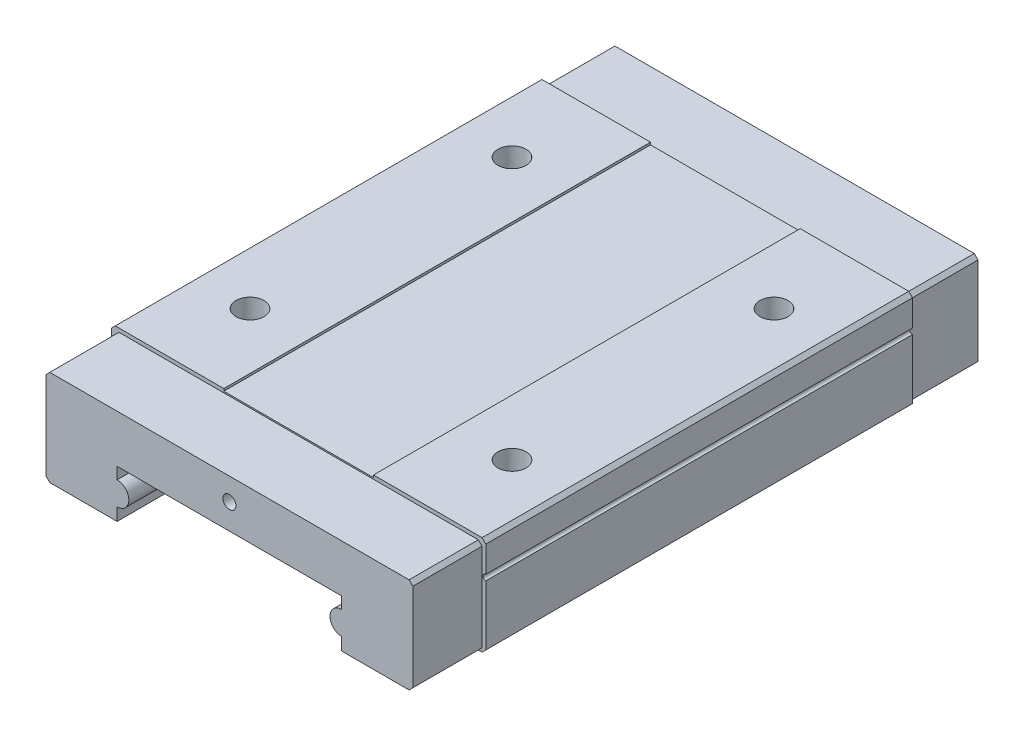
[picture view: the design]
ISO-10303-21;
HEADER;
FILE_DESCRIPTION(('STEP AP214'),'2;1');
FILE_NAME('part.step','',(''),(''),'','','');
FILE_SCHEMA(('AUTOMOTIVE_DESIGN { 1 0 10303 214 1 1 1 1 }'));
ENDSEC;
DATA;
#1=APPLICATION_CONTEXT('core data for automotive mechanical design processes');
#2=APPLICATION_PROTOCOL_DEFINITION('international standard','automotive_design',2000,#1);
#3=PRODUCT_CONTEXT('',#1,'mechanical');
#4=PRODUCT('Part','Part','',(#3));
#5=PRODUCT_RELATED_PRODUCT_CATEGORY('part','',(#4));
#6=PRODUCT_DEFINITION_FORMATION('','',#4);
#7=PRODUCT_DEFINITION_CONTEXT('part definition',#1,'design');
#8=PRODUCT_DEFINITION('design','',#6,#7);
#9=PRODUCT_DEFINITION_SHAPE('','',#8);
#10=(LENGTH_UNIT() NAMED_UNIT(*) SI_UNIT(.MILLI.,.METRE.));
#11=(NAMED_UNIT(*) PLANE_ANGLE_UNIT() SI_UNIT($,.RADIAN.));
#12=(NAMED_UNIT(*) SI_UNIT($,.STERADIAN.) SOLID_ANGLE_UNIT());
#13=UNCERTAINTY_MEASURE_WITH_UNIT(LENGTH_MEASURE(1.E-05),#10,'distance_accuracy_value','');
#14=(GEOMETRIC_REPRESENTATION_CONTEXT(3) GLOBAL_UNCERTAINTY_ASSIGNED_CONTEXT((#13)) GLOBAL_UNIT_ASSIGNED_CONTEXT((#10,
#11,#12)) REPRESENTATION_CONTEXT('',''));
#15=CARTESIAN_POINT('',(0.,0.,0.));
#16=DIRECTION('',(0.,0.,1.));
#17=DIRECTION('',(1.,0.,0.));
#18=AXIS2_PLACEMENT_3D('',#15,#16,#17);
#19=CARTESIAN_POINT('',(-14.,10.4000538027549,-14.));
#20=DIRECTION('',(0.,1.,0.));
#21=DIRECTION('',(0.,0.,1.));
#22=AXIS2_PLACEMENT_3D('',#19,#20,#21);
#23=CONICAL_SURFACE('',#22,1.49996298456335,0.785367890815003);
#24=CARTESIAN_POINT('',(-14.,8.89999999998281,-14.));
#25=VERTEX_POINT('',#24);
#26=VERTEX_LOOP('',#25);
#27=FACE_BOUND('',#26,.T.);
#28=CARTESIAN_POINT('',(-14.,10.4000908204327,-14.));
#29=DIRECTION('',(0.,1.,0.));
#30=DIRECTION('',(0.,0.,1.));
#31=AXIS2_PLACEMENT_3D('',#28,#29,#30);
#32=CIRCLE('',#31,1.5);
#33=CARTESIAN_POINT('',(-14.,10.4000908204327,-12.5));
#34=VERTEX_POINT('',#33);
#35=EDGE_CURVE('E20',#34,#34,#32,.T.);
#36=ORIENTED_EDGE('',*,*,#35,.T.);
#37=EDGE_LOOP('',(#36));
#38=FACE_BOUND('',#37,.T.);
#39=ADVANCED_FACE('F17',(#27,#38),#23,.F.);
#40=CARTESIAN_POINT('',(-14.,10.4000538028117,14.));
#41=DIRECTION('',(0.,1.,0.));
#42=DIRECTION('',(0.,0.,1.));
#43=AXIS2_PLACEMENT_3D('',#40,#41,#42);
#44=CONICAL_SURFACE('',#43,1.49996298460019,0.785367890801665);
#45=CARTESIAN_POINT('',(-14.,8.89999999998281,14.));
#46=VERTEX_POINT('',#45);
#47=VERTEX_LOOP('',#46);
#48=FACE_BOUND('',#47,.T.);
#49=CARTESIAN_POINT('',(-14.,10.4000908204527,14.));
#50=DIRECTION('',(0.,1.,0.));
#51=DIRECTION('',(0.,0.,1.));
#52=AXIS2_PLACEMENT_3D('',#49,#50,#51);
#53=CIRCLE('',#52,1.5);
#54=CARTESIAN_POINT('',(-14.,10.4000908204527,15.5));
#55=VERTEX_POINT('',#54);
#56=EDGE_CURVE('E369',#55,#55,#53,.T.);
#57=ORIENTED_EDGE('',*,*,#56,.T.);
#58=EDGE_LOOP('',(#57));
#59=FACE_BOUND('',#58,.T.);
#60=ADVANCED_FACE('F1261',(#48,#59),#44,.F.);
#61=CARTESIAN_POINT('',(14.,10.4000538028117,14.));
#62=DIRECTION('',(0.,1.,0.));
#63=DIRECTION('',(0.,0.,1.));
#64=AXIS2_PLACEMENT_3D('',#61,#62,#63);
#65=CONICAL_SURFACE('',#64,1.49996298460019,0.785367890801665);
#66=CARTESIAN_POINT('',(14.,8.89999999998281,14.));
#67=VERTEX_POINT('',#66);
#68=VERTEX_LOOP('',#67);
#69=FACE_BOUND('',#68,.T.);
#70=CARTESIAN_POINT('',(14.,10.4000908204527,14.));
#71=DIRECTION('',(0.,1.,0.));
#72=DIRECTION('',(0.,0.,1.));
#73=AXIS2_PLACEMENT_3D('',#70,#71,#72);
#74=CIRCLE('',#73,1.5);
#75=CARTESIAN_POINT('',(14.,10.4000908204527,15.5));
#76=VERTEX_POINT('',#75);
#77=EDGE_CURVE('E362',#76,#76,#74,.T.);
#78=ORIENTED_EDGE('',*,*,#77,.T.);
#79=EDGE_LOOP('',(#78));
#80=FACE_BOUND('',#79,.T.);
#81=ADVANCED_FACE('F440',(#69,#80),#65,.F.);
#82=CARTESIAN_POINT('',(14.,10.4000538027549,-14.));
#83=DIRECTION('',(0.,1.,0.));
#84=DIRECTION('',(0.,0.,1.));
#85=AXIS2_PLACEMENT_3D('',#82,#83,#84);
#86=CONICAL_SURFACE('',#85,1.49996298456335,0.785367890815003);
#87=CARTESIAN_POINT('',(14.,8.89999999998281,-14.));
#88=VERTEX_POINT('',#87);
#89=VERTEX_LOOP('',#88);
#90=FACE_BOUND('',#89,.T.);
#91=CARTESIAN_POINT('',(14.,10.4000908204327,-14.));
#92=DIRECTION('',(0.,1.,0.));
#93=DIRECTION('',(0.,0.,1.));
#94=AXIS2_PLACEMENT_3D('',#91,#92,#93);
#95=CIRCLE('',#94,1.5);
#96=CARTESIAN_POINT('',(14.,10.4000908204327,-12.5));
#97=VERTEX_POINT('',#96);
#98=EDGE_CURVE('E360',#97,#97,#95,.T.);
#99=ORIENTED_EDGE('',*,*,#98,.T.);
#100=EDGE_LOOP('',(#99));
#101=FACE_BOUND('',#100,.T.);
#102=ADVANCED_FACE('F426',(#90,#101),#86,.F.);
#103=CARTESIAN_POINT('',(-14.,14.,-14.));
#104=DIRECTION('',(0.,1.,0.));
#105=DIRECTION('',(0.,0.,1.));
#106=AXIS2_PLACEMENT_3D('',#103,#104,#105);
#107=CYLINDRICAL_SURFACE('',#106,1.5);
#108=CARTESIAN_POINT('',(-14.,14.,-14.));
#109=DIRECTION('',(0.,1.,0.));
#110=DIRECTION('',(0.,0.,1.));
#111=AXIS2_PLACEMENT_3D('',#108,#109,#110);
#112=CIRCLE('',#111,1.5);
#113=CARTESIAN_POINT('',(-14.,14.,-12.5));
#114=VERTEX_POINT('',#113);
#115=EDGE_CURVE('E293',#114,#114,#112,.F.);
#116=ORIENTED_EDGE('',*,*,#115,.F.);
#117=EDGE_LOOP('',(#116));
#118=FACE_BOUND('',#117,.T.);
#119=ORIENTED_EDGE('',*,*,#35,.F.);
#120=EDGE_LOOP('',(#119));
#121=FACE_BOUND('',#120,.T.);
#122=ADVANCED_FACE('F421',(#118,#121),#107,.F.);
#123=CARTESIAN_POINT('',(-14.,14.,14.));
#124=DIRECTION('',(0.,1.,0.));
#125=DIRECTION('',(0.,0.,1.));
#126=AXIS2_PLACEMENT_3D('',#123,#124,#125);
#127=CYLINDRICAL_SURFACE('',#126,1.5);
#128=CARTESIAN_POINT('',(-14.,14.,14.));
#129=DIRECTION('',(0.,1.,0.));
#130=DIRECTION('',(0.,0.,1.));
#131=AXIS2_PLACEMENT_3D('',#128,#129,#130);
#132=CIRCLE('',#131,1.5);
#133=CARTESIAN_POINT('',(-14.,14.,15.5));
#134=VERTEX_POINT('',#133);
#135=EDGE_CURVE('E288',#134,#134,#132,.F.);
#136=ORIENTED_EDGE('',*,*,#135,.F.);
#137=EDGE_LOOP('',(#136));
#138=FACE_BOUND('',#137,.T.);
#139=ORIENTED_EDGE('',*,*,#56,.F.);
#140=EDGE_LOOP('',(#139));
#141=FACE_BOUND('',#140,.T.);
#142=ADVANCED_FACE('F422',(#138,#141),#127,.F.);
#143=CARTESIAN_POINT('',(-8.,14.,22.8));
#144=DIRECTION('',(-1.,0.,0.));
#145=DIRECTION('',(0.,0.,1.));
#146=AXIS2_PLACEMENT_3D('',#143,#144,#145);
#147=PLANE('',#146);
#148=DIRECTION('',(0.,0.,1.));
#149=VECTOR('',#148,1.);
#150=CARTESIAN_POINT('',(-8.,14.,30.2));
#151=LINE('',#150,#149);
#152=CARTESIAN_POINT('',(-8.,14.,22.8));
#153=VERTEX_POINT('',#152);
#154=CARTESIAN_POINT('',(-8.,14.,-22.8));
#155=VERTEX_POINT('',#154);
#156=EDGE_CURVE('E287',#153,#155,#151,.F.);
#157=ORIENTED_EDGE('',*,*,#156,.F.);
#158=DIRECTION('',(0.,1.,0.));
#159=VECTOR('',#158,1.);
#160=CARTESIAN_POINT('',(-8.,14.,22.8));
#161=LINE('',#160,#159);
#162=CARTESIAN_POINT('',(-8.,13.75,22.8));
#163=VERTEX_POINT('',#162);
#164=EDGE_CURVE('E370',#163,#153,#161,.T.);
#165=ORIENTED_EDGE('',*,*,#164,.F.);
#166=DIRECTION('',(0.,0.,1.));
#167=VECTOR('',#166,1.);
#168=CARTESIAN_POINT('',(-8.,13.75,22.8));
#169=LINE('',#168,#167);
#170=CARTESIAN_POINT('',(-8.,13.75,-22.8));
#171=VERTEX_POINT('',#170);
#172=EDGE_CURVE('E289',#171,#163,#169,.T.);
#173=ORIENTED_EDGE('',*,*,#172,.F.);
#174=DIRECTION('',(0.,1.,0.));
#175=VECTOR('',#174,1.);
#176=CARTESIAN_POINT('',(-8.,14.,-22.8));
#177=LINE('',#176,#175);
#178=EDGE_CURVE('E364',#155,#171,#177,.F.);
#179=ORIENTED_EDGE('',*,*,#178,.F.);
#180=EDGE_LOOP('',(#157,#165,#173,#179));
#181=FACE_BOUND('',#180,.T.);
#182=ADVANCED_FACE('F432',(#181),#147,.F.);
#183=CARTESIAN_POINT('',(8.,14.,22.8));
#184=DIRECTION('',(-1.,0.,0.));
#185=DIRECTION('',(0.,0.,1.));
#186=AXIS2_PLACEMENT_3D('',#183,#184,#185);
#187=PLANE('',#186);
#188=DIRECTION('',(0.,1.,0.));
#189=VECTOR('',#188,1.);
#190=CARTESIAN_POINT('',(8.,14.,-22.8));
#191=LINE('',#190,#189);
#192=CARTESIAN_POINT('',(8.,14.,-22.8));
#193=VERTEX_POINT('',#192);
#194=CARTESIAN_POINT('',(8.,13.75,-22.8));
#195=VERTEX_POINT('',#194);
#196=EDGE_CURVE('E358',#193,#195,#191,.F.);
#197=ORIENTED_EDGE('',*,*,#196,.T.);
#198=DIRECTION('',(0.,0.,1.));
#199=VECTOR('',#198,1.);
#200=CARTESIAN_POINT('',(8.,13.75,22.8));
#201=LINE('',#200,#199);
#202=CARTESIAN_POINT('',(8.,13.75,22.8));
#203=VERTEX_POINT('',#202);
#204=EDGE_CURVE('E284',#203,#195,#201,.F.);
#205=ORIENTED_EDGE('',*,*,#204,.F.);
#206=DIRECTION('',(0.,1.,0.));
#207=VECTOR('',#206,1.);
#208=CARTESIAN_POINT('',(8.,14.,22.8));
#209=LINE('',#208,#207);
#210=CARTESIAN_POINT('',(8.,14.,22.8));
#211=VERTEX_POINT('',#210);
#212=EDGE_CURVE('E361',#203,#211,#209,.T.);
#213=ORIENTED_EDGE('',*,*,#212,.T.);
#214=DIRECTION('',(0.,0.,1.));
#215=VECTOR('',#214,1.);
#216=CARTESIAN_POINT('',(8.,14.,30.2));
#217=LINE('',#216,#215);
#218=EDGE_CURVE('E279',#193,#211,#217,.T.);
#219=ORIENTED_EDGE('',*,*,#218,.F.);
#220=EDGE_LOOP('',(#197,#205,#213,#219));
#221=FACE_BOUND('',#220,.T.);
#222=ADVANCED_FACE('F613',(#221),#187,.T.);
#223=CARTESIAN_POINT('',(14.,14.,14.));
#224=DIRECTION('',(0.,1.,0.));
#225=DIRECTION('',(0.,0.,1.));
#226=AXIS2_PLACEMENT_3D('',#223,#224,#225);
#227=CYLINDRICAL_SURFACE('',#226,1.5);
#228=CARTESIAN_POINT('',(14.,14.,14.));
#229=DIRECTION('',(0.,1.,0.));
#230=DIRECTION('',(0.,0.,1.));
#231=AXIS2_PLACEMENT_3D('',#228,#229,#230);
#232=CIRCLE('',#231,1.5);
#233=CARTESIAN_POINT('',(14.,14.,15.5));
#234=VERTEX_POINT('',#233);
#235=EDGE_CURVE('E281',#234,#234,#232,.F.);
#236=ORIENTED_EDGE('',*,*,#235,.F.);
#237=EDGE_LOOP('',(#236));
#238=FACE_BOUND('',#237,.T.);
#239=ORIENTED_EDGE('',*,*,#77,.F.);
#240=EDGE_LOOP('',(#239));
#241=FACE_BOUND('',#240,.T.);
#242=ADVANCED_FACE('F608',(#238,#241),#227,.F.);
#243=CARTESIAN_POINT('',(14.,14.,-14.));
#244=DIRECTION('',(0.,1.,0.));
#245=DIRECTION('',(0.,0.,1.));
#246=AXIS2_PLACEMENT_3D('',#243,#244,#245);
#247=CYLINDRICAL_SURFACE('',#246,1.5);
#248=CARTESIAN_POINT('',(14.,14.,-14.));
#249=DIRECTION('',(0.,1.,0.));
#250=DIRECTION('',(0.,0.,1.));
#251=AXIS2_PLACEMENT_3D('',#248,#249,#250);
#252=CIRCLE('',#251,1.5);
#253=CARTESIAN_POINT('',(14.,14.,-12.5));
#254=VERTEX_POINT('',#253);
#255=EDGE_CURVE('E274',#254,#254,#252,.F.);
#256=ORIENTED_EDGE('',*,*,#255,.F.);
#257=EDGE_LOOP('',(#256));
#258=FACE_BOUND('',#257,.T.);
#259=ORIENTED_EDGE('',*,*,#98,.F.);
#260=EDGE_LOOP('',(#259));
#261=FACE_BOUND('',#260,.T.);
#262=ADVANCED_FACE('F607',(#258,#261),#247,.F.);
#263=CARTESIAN_POINT('',(19.6,14.,30.2));
#264=DIRECTION('',(-0.707106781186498,-0.707106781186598,0.));
#265=DIRECTION('',(0.707106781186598,-0.707106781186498,0.));
#266=AXIS2_PLACEMENT_3D('',#263,#264,#265);
#267=PLANE('',#266);
#268=DIRECTION('',(0.707106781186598,-0.707106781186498,0.));
#269=VECTOR('',#268,1.);
#270=CARTESIAN_POINT('',(19.6,14.,-22.8));
#271=LINE('',#270,#269);
#272=CARTESIAN_POINT('',(19.6,14.,-22.8));
#273=VERTEX_POINT('',#272);
#274=CARTESIAN_POINT('',(20.,13.6,-22.8));
#275=VERTEX_POINT('',#274);
#276=EDGE_CURVE('E212',#273,#275,#271,.T.);
#277=ORIENTED_EDGE('',*,*,#276,.F.);
#278=DIRECTION('',(0.,0.,1.));
#279=VECTOR('',#278,1.);
#280=CARTESIAN_POINT('',(19.6,14.,30.2));
#281=LINE('',#280,#279);
#282=CARTESIAN_POINT('',(19.6,14.,22.8));
#283=VERTEX_POINT('',#282);
#284=EDGE_CURVE('E282',#283,#273,#281,.F.);
#285=ORIENTED_EDGE('',*,*,#284,.F.);
#286=DIRECTION('',(0.707106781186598,-0.707106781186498,0.));
#287=VECTOR('',#286,1.);
#288=CARTESIAN_POINT('',(19.6,14.,22.8));
#289=LINE('',#288,#287);
#290=CARTESIAN_POINT('',(20.,13.6,22.8));
#291=VERTEX_POINT('',#290);
#292=EDGE_CURVE('E352',#291,#283,#289,.F.);
#293=ORIENTED_EDGE('',*,*,#292,.F.);
#294=DIRECTION('',(0.,0.,-1.));
#295=VECTOR('',#294,1.);
#296=CARTESIAN_POINT('',(20.,13.6,30.2));
#297=LINE('',#296,#295);
#298=EDGE_CURVE('E275',#275,#291,#297,.F.);
#299=ORIENTED_EDGE('',*,*,#298,.F.);
#300=EDGE_LOOP('',(#277,#285,#293,#299));
#301=FACE_BOUND('',#300,.T.);
#302=ADVANCED_FACE('F602',(#301),#267,.F.);
#303=CARTESIAN_POINT('',(20.,10.5,30.2));
#304=DIRECTION('',(0.,0.,-1.));
#305=DIRECTION('',(-1.,0.,0.));
#306=AXIS2_PLACEMENT_3D('',#303,#304,#305);
#307=CYLINDRICAL_SURFACE('',#306,0.3);
#308=DIRECTION('',(0.,0.,-1.));
#309=VECTOR('',#308,1.);
#310=CARTESIAN_POINT('',(20.,10.8,30.2));
#311=LINE('',#310,#309);
#312=CARTESIAN_POINT('',(20.,10.8,22.8));
#313=VERTEX_POINT('',#312);
#314=CARTESIAN_POINT('',(20.,10.8,-22.8));
#315=VERTEX_POINT('',#314);
#316=EDGE_CURVE('E208',#313,#315,#311,.T.);
#317=ORIENTED_EDGE('',*,*,#316,.F.);
#318=CARTESIAN_POINT('',(20.,10.5,22.8));
#319=DIRECTION('',(0.,0.,-1.));
#320=DIRECTION('',(-1.,0.,0.));
#321=AXIS2_PLACEMENT_3D('',#318,#319,#320);
#322=CIRCLE('',#321,0.3);
#323=CARTESIAN_POINT('',(20.,10.2,22.8));
#324=VERTEX_POINT('',#323);
#325=EDGE_CURVE('E205',#324,#313,#322,.T.);
#326=ORIENTED_EDGE('',*,*,#325,.F.);
#327=DIRECTION('',(0.,0.,-1.));
#328=VECTOR('',#327,1.);
#329=CARTESIAN_POINT('',(20.,10.2,30.2));
#330=LINE('',#329,#328);
#331=CARTESIAN_POINT('',(20.,10.2,-22.8));
#332=VERTEX_POINT('',#331);
#333=EDGE_CURVE('E202',#332,#324,#330,.F.);
#334=ORIENTED_EDGE('',*,*,#333,.F.);
#335=CARTESIAN_POINT('',(20.,10.5,-22.8));
#336=DIRECTION('',(0.,0.,-1.));
#337=DIRECTION('',(-1.,0.,0.));
#338=AXIS2_PLACEMENT_3D('',#335,#336,#337);
#339=CIRCLE('',#338,0.3);
#340=EDGE_CURVE('E213',#315,#332,#339,.F.);
#341=ORIENTED_EDGE('',*,*,#340,.F.);
#342=EDGE_LOOP('',(#317,#326,#334,#341));
#343=FACE_BOUND('',#342,.T.);
#344=ADVANCED_FACE('F204',(#343),#307,.F.);
#345=CARTESIAN_POINT('',(-20.,13.6,30.2));
#346=DIRECTION('',(0.707106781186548,-0.707106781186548,0.));
#347=DIRECTION('',(0.707106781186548,0.707106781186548,0.));
#348=AXIS2_PLACEMENT_3D('',#345,#346,#347);
#349=PLANE('',#348);
#350=DIRECTION('',(0.707106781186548,0.707106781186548,0.));
#351=VECTOR('',#350,1.);
#352=CARTESIAN_POINT('',(-20.,13.6,-22.8));
#353=LINE('',#352,#351);
#354=CARTESIAN_POINT('',(-20.,13.6,-22.8));
#355=VERTEX_POINT('',#354);
#356=CARTESIAN_POINT('',(-19.6,14.,-22.8));
#357=VERTEX_POINT('',#356);
#358=EDGE_CURVE('E224',#355,#357,#353,.T.);
#359=ORIENTED_EDGE('',*,*,#358,.F.);
#360=DIRECTION('',(0.,0.,1.));
#361=VECTOR('',#360,1.);
#362=CARTESIAN_POINT('',(-20.,13.6,30.2));
#363=LINE('',#362,#361);
#364=CARTESIAN_POINT('',(-20.,13.6,22.8));
#365=VERTEX_POINT('',#364);
#366=EDGE_CURVE('E250',#365,#355,#363,.F.);
#367=ORIENTED_EDGE('',*,*,#366,.F.);
#368=DIRECTION('',(0.707106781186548,0.707106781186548,0.));
#369=VECTOR('',#368,1.);
#370=CARTESIAN_POINT('',(-20.,13.6,22.8));
#371=LINE('',#370,#369);
#372=CARTESIAN_POINT('',(-19.6,14.,22.8));
#373=VERTEX_POINT('',#372);
#374=EDGE_CURVE('E349',#373,#365,#371,.F.);
#375=ORIENTED_EDGE('',*,*,#374,.F.);
#376=DIRECTION('',(0.,0.,1.));
#377=VECTOR('',#376,1.);
#378=CARTESIAN_POINT('',(-19.6,14.,30.2));
#379=LINE('',#378,#377);
#380=EDGE_CURVE('E225',#357,#373,#379,.T.);
#381=ORIENTED_EDGE('',*,*,#380,.F.);
#382=EDGE_LOOP('',(#359,#367,#375,#381));
#383=FACE_BOUND('',#382,.T.);
#384=ADVANCED_FACE('F600',(#383),#349,.F.);
#385=CARTESIAN_POINT('',(20.,10.2,30.2));
#386=DIRECTION('',(1.,0.,0.));
#387=DIRECTION('',(0.,0.,-1.));
#388=AXIS2_PLACEMENT_3D('',#385,#386,#387);
#389=PLANE('',#388);
#390=ORIENTED_EDGE('',*,*,#333,.T.);
#391=DIRECTION('',(0.,1.,0.));
#392=VECTOR('',#391,1.);
#393=CARTESIAN_POINT('',(20.,14.,22.8));
#394=LINE('',#393,#392);
#395=CARTESIAN_POINT('',(20.,3.8,22.8));
#396=VERTEX_POINT('',#395);
#397=EDGE_CURVE('E217',#396,#324,#394,.T.);
#398=ORIENTED_EDGE('',*,*,#397,.F.);
#399=DIRECTION('',(0.,0.,1.));
#400=VECTOR('',#399,1.);
#401=CARTESIAN_POINT('',(20.,3.8,30.2));
#402=LINE('',#401,#400);
#403=CARTESIAN_POINT('',(20.,3.8,-22.8));
#404=VERTEX_POINT('',#403);
#405=EDGE_CURVE('E305',#396,#404,#402,.F.);
#406=ORIENTED_EDGE('',*,*,#405,.T.);
#407=DIRECTION('',(0.,1.,0.));
#408=VECTOR('',#407,1.);
#409=CARTESIAN_POINT('',(20.,14.,-22.8));
#410=LINE('',#409,#408);
#411=EDGE_CURVE('E222',#332,#404,#410,.F.);
#412=ORIENTED_EDGE('',*,*,#411,.F.);
#413=EDGE_LOOP('',(#390,#398,#406,#412));
#414=FACE_BOUND('',#413,.T.);
#415=ADVANCED_FACE('F220',(#414),#389,.T.);
#416=CARTESIAN_POINT('',(-20.,14.,30.2));
#417=DIRECTION('',(0.,1.,0.));
#418=DIRECTION('',(0.,0.,1.));
#419=AXIS2_PLACEMENT_3D('',#416,#417,#418);
#420=PLANE('',#419);
#421=ORIENTED_EDGE('',*,*,#135,.T.);
#422=EDGE_LOOP('',(#421));
#423=FACE_BOUND('',#422,.T.);
#424=ORIENTED_EDGE('',*,*,#115,.T.);
#425=EDGE_LOOP('',(#424));
#426=FACE_BOUND('',#425,.T.);
#427=ORIENTED_EDGE('',*,*,#156,.T.);
#428=DIRECTION('',(-1.,0.,0.));
#429=VECTOR('',#428,1.);
#430=CARTESIAN_POINT('',(20.,14.,-22.8));
#431=LINE('',#430,#429);
#432=EDGE_CURVE('E698',#357,#155,#431,.F.);
#433=ORIENTED_EDGE('',*,*,#432,.F.);
#434=ORIENTED_EDGE('',*,*,#380,.T.);
#435=DIRECTION('',(1.,0.,0.));
#436=VECTOR('',#435,1.);
#437=CARTESIAN_POINT('',(-20.,14.,22.8));
#438=LINE('',#437,#436);
#439=EDGE_CURVE('E629',#153,#373,#438,.F.);
#440=ORIENTED_EDGE('',*,*,#439,.F.);
#441=EDGE_LOOP('',(#427,#433,#434,#440));
#442=FACE_BOUND('',#441,.T.);
#443=ADVANCED_FACE('F587',(#423,#426,#442),#420,.T.);
#444=CARTESIAN_POINT('',(-20.,13.75,22.8));
#445=DIRECTION('',(0.,1.,0.));
#446=DIRECTION('',(0.,0.,1.));
#447=AXIS2_PLACEMENT_3D('',#444,#445,#446);
#448=PLANE('',#447);
#449=ORIENTED_EDGE('',*,*,#204,.T.);
#450=DIRECTION('',(-1.,0.,0.));
#451=VECTOR('',#450,1.);
#452=CARTESIAN_POINT('',(20.,13.75,-22.8));
#453=LINE('',#452,#451);
#454=EDGE_CURVE('E378',#171,#195,#453,.F.);
#455=ORIENTED_EDGE('',*,*,#454,.F.);
#456=ORIENTED_EDGE('',*,*,#172,.T.);
#457=DIRECTION('',(1.,0.,0.));
#458=VECTOR('',#457,1.);
#459=CARTESIAN_POINT('',(-20.,13.75,22.8));
#460=LINE('',#459,#458);
#461=EDGE_CURVE('E382',#203,#163,#460,.F.);
#462=ORIENTED_EDGE('',*,*,#461,.F.);
#463=EDGE_LOOP('',(#449,#455,#456,#462));
#464=FACE_BOUND('',#463,.T.);
#465=ADVANCED_FACE('F588',(#464),#448,.T.);
#466=CARTESIAN_POINT('',(-20.,14.,30.2));
#467=DIRECTION('',(0.,1.,0.));
#468=DIRECTION('',(0.,0.,1.));
#469=AXIS2_PLACEMENT_3D('',#466,#467,#468);
#470=PLANE('',#469);
#471=ORIENTED_EDGE('',*,*,#255,.T.);
#472=EDGE_LOOP('',(#471));
#473=FACE_BOUND('',#472,.T.);
#474=ORIENTED_EDGE('',*,*,#235,.T.);
#475=EDGE_LOOP('',(#474));
#476=FACE_BOUND('',#475,.T.);
#477=ORIENTED_EDGE('',*,*,#218,.T.);
#478=DIRECTION('',(1.,0.,0.));
#479=VECTOR('',#478,1.);
#480=CARTESIAN_POINT('',(-20.,14.,22.8));
#481=LINE('',#480,#479);
#482=EDGE_CURVE('E235',#283,#211,#481,.F.);
#483=ORIENTED_EDGE('',*,*,#482,.F.);
#484=ORIENTED_EDGE('',*,*,#284,.T.);
#485=DIRECTION('',(-1.,0.,0.));
#486=VECTOR('',#485,1.);
#487=CARTESIAN_POINT('',(20.,14.,-22.8));
#488=LINE('',#487,#486);
#489=EDGE_CURVE('E372',#193,#273,#488,.F.);
#490=ORIENTED_EDGE('',*,*,#489,.F.);
#491=EDGE_LOOP('',(#477,#483,#484,#490));
#492=FACE_BOUND('',#491,.T.);
#493=ADVANCED_FACE('F582',(#473,#476,#492),#470,.T.);
#494=CARTESIAN_POINT('',(20.,14.,30.2));
#495=DIRECTION('',(1.,0.,0.));
#496=DIRECTION('',(0.,0.,-1.));
#497=AXIS2_PLACEMENT_3D('',#494,#495,#496);
#498=PLANE('',#497);
#499=ORIENTED_EDGE('',*,*,#316,.T.);
#500=DIRECTION('',(0.,1.,0.));
#501=VECTOR('',#500,1.);
#502=CARTESIAN_POINT('',(20.,14.,-22.8));
#503=LINE('',#502,#501);
#504=EDGE_CURVE('E380',#275,#315,#503,.F.);
#505=ORIENTED_EDGE('',*,*,#504,.F.);
#506=ORIENTED_EDGE('',*,*,#298,.T.);
#507=DIRECTION('',(0.,1.,0.));
#508=VECTOR('',#507,1.);
#509=CARTESIAN_POINT('',(20.,14.,22.8));
#510=LINE('',#509,#508);
#511=EDGE_CURVE('E230',#313,#291,#510,.T.);
#512=ORIENTED_EDGE('',*,*,#511,.F.);
#513=EDGE_LOOP('',(#499,#505,#506,#512));
#514=FACE_BOUND('',#513,.T.);
#515=ADVANCED_FACE('F579',(#514),#498,.T.);
#516=CARTESIAN_POINT('',(-20.,3.4,30.2));
#517=DIRECTION('',(-1.,0.,0.));
#518=DIRECTION('',(0.,0.,1.));
#519=AXIS2_PLACEMENT_3D('',#516,#517,#518);
#520=PLANE('',#519);
#521=DIRECTION('',(0.,0.,1.));
#522=VECTOR('',#521,1.);
#523=CARTESIAN_POINT('',(-20.,3.79999999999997,30.2));
#524=LINE('',#523,#522);
#525=CARTESIAN_POINT('',(-20.,3.79999999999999,-22.8));
#526=VERTEX_POINT('',#525);
#527=CARTESIAN_POINT('',(-20.,3.79999999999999,22.8));
#528=VERTEX_POINT('',#527);
#529=EDGE_CURVE('E716',#526,#528,#524,.T.);
#530=ORIENTED_EDGE('',*,*,#529,.T.);
#531=DIRECTION('',(0.,1.,0.));
#532=VECTOR('',#531,1.);
#533=CARTESIAN_POINT('',(-20.,14.,22.8));
#534=LINE('',#533,#532);
#535=EDGE_CURVE('E635',#365,#528,#534,.F.);
#536=ORIENTED_EDGE('',*,*,#535,.F.);
#537=ORIENTED_EDGE('',*,*,#366,.T.);
#538=DIRECTION('',(0.,1.,0.));
#539=VECTOR('',#538,1.);
#540=CARTESIAN_POINT('',(-20.,14.,-22.8));
#541=LINE('',#540,#539);
#542=EDGE_CURVE('E691',#526,#355,#541,.T.);
#543=ORIENTED_EDGE('',*,*,#542,.F.);
#544=EDGE_LOOP('',(#530,#536,#537,#543));
#545=FACE_BOUND('',#544,.T.);
#546=ADVANCED_FACE('F573',(#545),#520,.T.);
#547=CARTESIAN_POINT('',(19.2,13.6,30.2));
#548=DIRECTION('',(0.707106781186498,0.707106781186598,0.));
#549=DIRECTION('',(-0.707106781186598,0.707106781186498,0.));
#550=AXIS2_PLACEMENT_3D('',#547,#548,#549);
#551=PLANE('',#550);
#552=DIRECTION('',(0.,0.,1.));
#553=VECTOR('',#552,1.);
#554=CARTESIAN_POINT('',(19.2,13.6,30.2));
#555=LINE('',#554,#553);
#556=CARTESIAN_POINT('',(19.2,13.6,30.2));
#557=VERTEX_POINT('',#556);
#558=CARTESIAN_POINT('',(19.2,13.6,22.8));
#559=VERTEX_POINT('',#558);
#560=EDGE_CURVE('E740',#557,#559,#555,.F.);
#561=ORIENTED_EDGE('',*,*,#560,.F.);
#562=DIRECTION('',(-0.707106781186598,0.707106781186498,0.));
#563=VECTOR('',#562,1.);
#564=CARTESIAN_POINT('',(19.2,13.6,30.2));
#565=LINE('',#564,#563);
#566=CARTESIAN_POINT('',(19.6,13.2,30.2));
#567=VERTEX_POINT('',#566);
#568=EDGE_CURVE('E243',#557,#567,#565,.F.);
#569=ORIENTED_EDGE('',*,*,#568,.T.);
#570=DIRECTION('',(0.,0.,1.));
#571=VECTOR('',#570,1.);
#572=CARTESIAN_POINT('',(19.6,13.2,30.2));
#573=LINE('',#572,#571);
#574=CARTESIAN_POINT('',(19.6,13.2,22.8));
#575=VERTEX_POINT('',#574);
#576=EDGE_CURVE('E722',#567,#575,#573,.F.);
#577=ORIENTED_EDGE('',*,*,#576,.T.);
#578=DIRECTION('',(0.707106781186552,-0.707106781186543,0.));
#579=VECTOR('',#578,1.);
#580=CARTESIAN_POINT('',(19.2,13.6,22.8));
#581=LINE('',#580,#579);
#582=EDGE_CURVE('E328',#559,#575,#581,.T.);
#583=ORIENTED_EDGE('',*,*,#582,.F.);
#584=EDGE_LOOP('',(#561,#569,#577,#583));
#585=FACE_BOUND('',#584,.T.);
#586=ADVANCED_FACE('F569',(#585),#551,.T.);
#587=CARTESIAN_POINT('',(-19.6,13.2,30.2));
#588=DIRECTION('',(0.707106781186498,-0.707106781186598,0.));
#589=DIRECTION('',(0.707106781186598,0.707106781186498,0.));
#590=AXIS2_PLACEMENT_3D('',#587,#588,#589);
#591=PLANE('',#590);
#592=DIRECTION('',(0.707106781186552,0.707106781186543,0.));
#593=VECTOR('',#592,1.);
#594=CARTESIAN_POINT('',(-19.6,13.2,22.8));
#595=LINE('',#594,#593);
#596=CARTESIAN_POINT('',(-19.6,13.2,22.8));
#597=VERTEX_POINT('',#596);
#598=CARTESIAN_POINT('',(-19.2,13.6,22.8));
#599=VERTEX_POINT('',#598);
#600=EDGE_CURVE('E643',#597,#599,#595,.T.);
#601=ORIENTED_EDGE('',*,*,#600,.F.);
#602=DIRECTION('',(0.,0.,1.));
#603=VECTOR('',#602,1.);
#604=CARTESIAN_POINT('',(-19.6,13.2,30.2));
#605=LINE('',#604,#603);
#606=CARTESIAN_POINT('',(-19.6,13.2,30.2));
#607=VERTEX_POINT('',#606);
#608=EDGE_CURVE('E748',#607,#597,#605,.F.);
#609=ORIENTED_EDGE('',*,*,#608,.F.);
#610=DIRECTION('',(0.707106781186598,0.707106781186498,0.));
#611=VECTOR('',#610,1.);
#612=CARTESIAN_POINT('',(-19.6,13.2,30.2));
#613=LINE('',#612,#611);
#614=CARTESIAN_POINT('',(-19.2,13.6,30.2));
#615=VERTEX_POINT('',#614);
#616=EDGE_CURVE('E232',#615,#607,#613,.F.);
#617=ORIENTED_EDGE('',*,*,#616,.F.);
#618=DIRECTION('',(0.,0.,1.));
#619=VECTOR('',#618,1.);
#620=CARTESIAN_POINT('',(-19.2,13.6,30.2));
#621=LINE('',#620,#619);
#622=EDGE_CURVE('E732',#599,#615,#621,.T.);
#623=ORIENTED_EDGE('',*,*,#622,.F.);
#624=EDGE_LOOP('',(#601,#609,#617,#623));
#625=FACE_BOUND('',#624,.T.);
#626=ADVANCED_FACE('F566',(#625),#591,.F.);
#627=CARTESIAN_POINT('',(-20.,14.,22.8));
#628=DIRECTION('',(0.,0.,1.));
#629=DIRECTION('',(1.,0.,0.));
#630=AXIS2_PLACEMENT_3D('',#627,#628,#629);
#631=PLANE('',#630);
#632=ORIENTED_EDGE('',*,*,#582,.T.);
#633=DIRECTION('',(0.,1.,0.));
#634=VECTOR('',#633,1.);
#635=CARTESIAN_POINT('',(19.6,3.4,22.8));
#636=LINE('',#635,#634);
#637=CARTESIAN_POINT('',(19.6,3.8,22.8));
#638=VERTEX_POINT('',#637);
#639=EDGE_CURVE('E728',#575,#638,#636,.F.);
#640=ORIENTED_EDGE('',*,*,#639,.T.);
#641=DIRECTION('',(0.707106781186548,0.707106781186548,0.));
#642=VECTOR('',#641,1.);
#643=CARTESIAN_POINT('',(19.6,3.8,22.8));
#644=LINE('',#643,#642);
#645=CARTESIAN_POINT('',(19.2,3.4,22.8));
#646=VERTEX_POINT('',#645);
#647=EDGE_CURVE('E301',#646,#638,#644,.T.);
#648=ORIENTED_EDGE('',*,*,#647,.F.);
#649=DIRECTION('',(1.,0.,0.));
#650=VECTOR('',#649,1.);
#651=CARTESIAN_POINT('',(-20.,3.4,22.8));
#652=LINE('',#651,#650);
#653=CARTESIAN_POINT('',(19.6,3.4,22.8));
#654=VERTEX_POINT('',#653);
#655=EDGE_CURVE('E234',#646,#654,#652,.T.);
#656=ORIENTED_EDGE('',*,*,#655,.T.);
#657=DIRECTION('',(-0.707106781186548,-0.707106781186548,0.));
#658=VECTOR('',#657,1.);
#659=CARTESIAN_POINT('',(20.,3.8,22.8));
#660=LINE('',#659,#658);
#661=EDGE_CURVE('E229',#654,#396,#660,.F.);
#662=ORIENTED_EDGE('',*,*,#661,.T.);
#663=ORIENTED_EDGE('',*,*,#397,.T.);
#664=ORIENTED_EDGE('',*,*,#325,.T.);
#665=ORIENTED_EDGE('',*,*,#511,.T.);
#666=ORIENTED_EDGE('',*,*,#292,.T.);
#667=ORIENTED_EDGE('',*,*,#482,.T.);
#668=ORIENTED_EDGE('',*,*,#212,.F.);
#669=ORIENTED_EDGE('',*,*,#461,.T.);
#670=ORIENTED_EDGE('',*,*,#164,.T.);
#671=ORIENTED_EDGE('',*,*,#439,.T.);
#672=ORIENTED_EDGE('',*,*,#374,.T.);
#673=ORIENTED_EDGE('',*,*,#535,.T.);
#674=DIRECTION('',(-0.707106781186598,0.707106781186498,0.));
#675=VECTOR('',#674,1.);
#676=CARTESIAN_POINT('',(-19.6,3.4,22.8));
#677=LINE('',#676,#675);
#678=CARTESIAN_POINT('',(-19.6,3.4,22.8));
#679=VERTEX_POINT('',#678);
#680=EDGE_CURVE('E712',#528,#679,#677,.F.);
#681=ORIENTED_EDGE('',*,*,#680,.T.);
#682=DIRECTION('',(1.,0.,0.));
#683=VECTOR('',#682,1.);
#684=CARTESIAN_POINT('',(-20.,3.4,22.8));
#685=LINE('',#684,#683);
#686=CARTESIAN_POINT('',(-19.2,3.4,22.8));
#687=VERTEX_POINT('',#686);
#688=EDGE_CURVE('E631',#679,#687,#685,.T.);
#689=ORIENTED_EDGE('',*,*,#688,.T.);
#690=DIRECTION('',(-0.707106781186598,0.707106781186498,0.));
#691=VECTOR('',#690,1.);
#692=CARTESIAN_POINT('',(-19.2,3.4,22.8));
#693=LINE('',#692,#691);
#694=CARTESIAN_POINT('',(-19.6,3.79999999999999,22.8));
#695=VERTEX_POINT('',#694);
#696=EDGE_CURVE('E711',#687,#695,#693,.T.);
#697=ORIENTED_EDGE('',*,*,#696,.T.);
#698=DIRECTION('',(0.,1.,0.));
#699=VECTOR('',#698,1.);
#700=CARTESIAN_POINT('',(-19.6,3.4,22.8));
#701=LINE('',#700,#699);
#702=EDGE_CURVE('E647',#597,#695,#701,.F.);
#703=ORIENTED_EDGE('',*,*,#702,.F.);
#704=ORIENTED_EDGE('',*,*,#600,.T.);
#705=DIRECTION('',(1.,0.,0.));
#706=VECTOR('',#705,1.);
#707=CARTESIAN_POINT('',(-20.,13.6,22.8));
#708=LINE('',#707,#706);
#709=EDGE_CURVE('E739',#559,#599,#708,.F.);
#710=ORIENTED_EDGE('',*,*,#709,.F.);
#711=EDGE_LOOP('',(#632,#640,#648,#656,#662,#663,#664,#665,#666,#667,#668,#669,#670,#671,#672,
#673,#681,#689,#697,#703,#704,#710));
#712=FACE_BOUND('',#711,.T.);
#713=ADVANCED_FACE('F226',(#712),#631,.T.);
#714=CARTESIAN_POINT('',(0.,11.2,25.1999999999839));
#715=DIRECTION('',(0.,0.,1.));
#716=DIRECTION('',(1.,0.,0.));
#717=AXIS2_PLACEMENT_3D('',#714,#715,#716);
#718=CONICAL_SURFACE('',#717,0.699999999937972,1.0297442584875);
#719=CARTESIAN_POINT('',(-2.8421709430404E-11,11.2,24.7793975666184));
#720=VERTEX_POINT('',#719);
#721=VERTEX_LOOP('',#720);
#722=FACE_BOUND('',#721,.T.);
#723=CARTESIAN_POINT('',(0.,11.2,25.2));
#724=DIRECTION('',(0.,0.,-1.));
#725=DIRECTION('',(-1.,0.,0.));
#726=AXIS2_PLACEMENT_3D('',#723,#724,#725);
#727=CIRCLE('',#726,0.7);
#728=CARTESIAN_POINT('',(-0.7,11.2,25.2));
#729=VERTEX_POINT('',#728);
#730=EDGE_CURVE('E642',#729,#729,#727,.F.);
#731=ORIENTED_EDGE('',*,*,#730,.T.);
#732=EDGE_LOOP('',(#731));
#733=FACE_BOUND('',#732,.T.);
#734=ADVANCED_FACE('F560',(#722,#733),#718,.F.);
#735=CARTESIAN_POINT('',(20.,3.8,30.2));
#736=DIRECTION('',(-0.707106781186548,0.707106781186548,0.));
#737=DIRECTION('',(-0.707106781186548,-0.707106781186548,0.));
#738=AXIS2_PLACEMENT_3D('',#735,#736,#737);
#739=PLANE('',#738);
#740=DIRECTION('',(-0.707106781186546,-0.707106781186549,0.));
#741=VECTOR('',#740,1.);
#742=CARTESIAN_POINT('',(20.,3.8,-22.8));
#743=LINE('',#742,#741);
#744=CARTESIAN_POINT('',(19.6,3.4,-22.8));
#745=VERTEX_POINT('',#744);
#746=EDGE_CURVE('E296',#404,#745,#743,.T.);
#747=ORIENTED_EDGE('',*,*,#746,.F.);
#748=ORIENTED_EDGE('',*,*,#405,.F.);
#749=ORIENTED_EDGE('',*,*,#661,.F.);
#750=DIRECTION('',(0.,0.,-1.));
#751=VECTOR('',#750,1.);
#752=CARTESIAN_POINT('',(19.6,3.4,30.2));
#753=LINE('',#752,#751);
#754=EDGE_CURVE('E331',#745,#654,#753,.F.);
#755=ORIENTED_EDGE('',*,*,#754,.F.);
#756=EDGE_LOOP('',(#747,#748,#749,#755));
#757=FACE_BOUND('',#756,.T.);
#758=ADVANCED_FACE('F556',(#757),#739,.F.);
#759=CARTESIAN_POINT('',(19.6,3.8,30.2));
#760=DIRECTION('',(0.707106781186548,-0.707106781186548,0.));
#761=DIRECTION('',(0.707106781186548,0.707106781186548,0.));
#762=AXIS2_PLACEMENT_3D('',#759,#760,#761);
#763=PLANE('',#762);
#764=DIRECTION('',(0.,0.,1.));
#765=VECTOR('',#764,1.);
#766=CARTESIAN_POINT('',(19.6,3.8,30.2));
#767=LINE('',#766,#765);
#768=CARTESIAN_POINT('',(19.6,3.8,30.2));
#769=VERTEX_POINT('',#768);
#770=EDGE_CURVE('E735',#638,#769,#767,.T.);
#771=ORIENTED_EDGE('',*,*,#770,.T.);
#772=DIRECTION('',(0.707106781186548,0.707106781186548,0.));
#773=VECTOR('',#772,1.);
#774=CARTESIAN_POINT('',(19.6,3.8,30.2));
#775=LINE('',#774,#773);
#776=CARTESIAN_POINT('',(19.2,3.4,30.2));
#777=VERTEX_POINT('',#776);
#778=EDGE_CURVE('E341',#769,#777,#775,.F.);
#779=ORIENTED_EDGE('',*,*,#778,.T.);
#780=DIRECTION('',(0.,0.,-1.));
#781=VECTOR('',#780,1.);
#782=CARTESIAN_POINT('',(19.2,3.4,30.2));
#783=LINE('',#782,#781);
#784=EDGE_CURVE('E313',#646,#777,#783,.F.);
#785=ORIENTED_EDGE('',*,*,#784,.F.);
#786=ORIENTED_EDGE('',*,*,#647,.T.);
#787=EDGE_LOOP('',(#771,#779,#785,#786));
#788=FACE_BOUND('',#787,.T.);
#789=ADVANCED_FACE('F555',(#788),#763,.T.);
#790=CARTESIAN_POINT('',(12.,0.,55.));
#791=DIRECTION('',(-1.,0.,0.));
#792=DIRECTION('',(0.,0.,1.));
#793=AXIS2_PLACEMENT_3D('',#790,#791,#792);
#794=PLANE('',#793);
#795=DIRECTION('',(0.,0.,-1.));
#796=VECTOR('',#795,1.);
#797=CARTESIAN_POINT('',(12.,4.75,55.));
#798=LINE('',#797,#796);
#799=CARTESIAN_POINT('',(12.,4.75,-30.2));
#800=VERTEX_POINT('',#799);
#801=CARTESIAN_POINT('',(12.,4.75,30.2));
#802=VERTEX_POINT('',#801);
#803=EDGE_CURVE('E765',#800,#802,#798,.F.);
#804=ORIENTED_EDGE('',*,*,#803,.F.);
#805=DIRECTION('',(0.,1.,0.));
#806=VECTOR('',#805,1.);
#807=CARTESIAN_POINT('',(12.,0.,-30.2));
#808=LINE('',#807,#806);
#809=CARTESIAN_POINT('',(12.,3.4,-30.2));
#810=VERTEX_POINT('',#809);
#811=EDGE_CURVE('E661',#800,#810,#808,.F.);
#812=ORIENTED_EDGE('',*,*,#811,.T.);
#813=DIRECTION('',(0.,0.,-1.));
#814=VECTOR('',#813,1.);
#815=CARTESIAN_POINT('',(12.,3.4,30.2));
#816=LINE('',#815,#814);
#817=CARTESIAN_POINT('',(12.,3.4,30.2));
#818=VERTEX_POINT('',#817);
#819=EDGE_CURVE('E307',#818,#810,#816,.T.);
#820=ORIENTED_EDGE('',*,*,#819,.F.);
#821=DIRECTION('',(0.,1.,0.));
#822=VECTOR('',#821,1.);
#823=CARTESIAN_POINT('',(12.,0.,30.2));
#824=LINE('',#823,#822);
#825=EDGE_CURVE('E665',#818,#802,#824,.T.);
#826=ORIENTED_EDGE('',*,*,#825,.T.);
#827=EDGE_LOOP('',(#804,#812,#820,#826));
#828=FACE_BOUND('',#827,.T.);
#829=ADVANCED_FACE('F547',(#828),#794,.T.);
#830=CARTESIAN_POINT('',(19.2,3.4,30.2));
#831=DIRECTION('',(-0.707106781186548,0.707106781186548,0.));
#832=DIRECTION('',(-0.707106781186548,-0.707106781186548,0.));
#833=AXIS2_PLACEMENT_3D('',#830,#831,#832);
#834=PLANE('',#833);
#835=DIRECTION('',(0.707106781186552,0.707106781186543,0.));
#836=VECTOR('',#835,1.);
#837=CARTESIAN_POINT('',(19.2,3.4,-22.8));
#838=LINE('',#837,#836);
#839=CARTESIAN_POINT('',(19.2,3.4,-22.8));
#840=VERTEX_POINT('',#839);
#841=CARTESIAN_POINT('',(19.6,3.8,-22.8));
#842=VERTEX_POINT('',#841);
#843=EDGE_CURVE('E298',#840,#842,#838,.T.);
#844=ORIENTED_EDGE('',*,*,#843,.F.);
#845=DIRECTION('',(0.,0.,-1.));
#846=VECTOR('',#845,1.);
#847=CARTESIAN_POINT('',(19.2,3.4,30.2));
#848=LINE('',#847,#846);
#849=CARTESIAN_POINT('',(19.2,3.4,-30.2));
#850=VERTEX_POINT('',#849);
#851=EDGE_CURVE('E776',#850,#840,#848,.F.);
#852=ORIENTED_EDGE('',*,*,#851,.F.);
#853=DIRECTION('',(-0.707106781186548,-0.707106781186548,0.));
#854=VECTOR('',#853,1.);
#855=CARTESIAN_POINT('',(19.2,3.4,-30.2));
#856=LINE('',#855,#854);
#857=CARTESIAN_POINT('',(19.6,3.8,-30.2));
#858=VERTEX_POINT('',#857);
#859=EDGE_CURVE('E669',#858,#850,#856,.T.);
#860=ORIENTED_EDGE('',*,*,#859,.F.);
#861=DIRECTION('',(0.,0.,-1.));
#862=VECTOR('',#861,1.);
#863=CARTESIAN_POINT('',(19.6,3.8,-30.2));
#864=LINE('',#863,#862);
#865=EDGE_CURVE('E309',#842,#858,#864,.T.);
#866=ORIENTED_EDGE('',*,*,#865,.F.);
#867=EDGE_LOOP('',(#844,#852,#860,#866));
#868=FACE_BOUND('',#867,.T.);
#869=ADVANCED_FACE('F542',(#868),#834,.F.);
#870=CARTESIAN_POINT('',(19.6,13.2,-30.2));
#871=DIRECTION('',(-0.707106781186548,-0.707106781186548,0.));
#872=DIRECTION('',(0.707106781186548,-0.707106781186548,0.));
#873=AXIS2_PLACEMENT_3D('',#870,#871,#872);
#874=PLANE('',#873);
#875=DIRECTION('',(-0.707106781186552,0.707106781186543,0.));
#876=VECTOR('',#875,1.);
#877=CARTESIAN_POINT('',(19.6,13.2,-22.8));
#878=LINE('',#877,#876);
#879=CARTESIAN_POINT('',(19.6,13.2,-22.8));
#880=VERTEX_POINT('',#879);
#881=CARTESIAN_POINT('',(19.2,13.6,-22.8));
#882=VERTEX_POINT('',#881);
#883=EDGE_CURVE('E683',#880,#882,#878,.T.);
#884=ORIENTED_EDGE('',*,*,#883,.F.);
#885=DIRECTION('',(0.,0.,-1.));
#886=VECTOR('',#885,1.);
#887=CARTESIAN_POINT('',(19.6,13.2,-30.2));
#888=LINE('',#887,#886);
#889=CARTESIAN_POINT('',(19.6,13.2,-30.2));
#890=VERTEX_POINT('',#889);
#891=EDGE_CURVE('E785',#890,#880,#888,.F.);
#892=ORIENTED_EDGE('',*,*,#891,.F.);
#893=DIRECTION('',(0.707106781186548,-0.707106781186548,0.));
#894=VECTOR('',#893,1.);
#895=CARTESIAN_POINT('',(19.6,13.2,-30.2));
#896=LINE('',#895,#894);
#897=CARTESIAN_POINT('',(19.2,13.6,-30.2));
#898=VERTEX_POINT('',#897);
#899=EDGE_CURVE('E675',#898,#890,#896,.T.);
#900=ORIENTED_EDGE('',*,*,#899,.F.);
#901=DIRECTION('',(0.,0.,1.));
#902=VECTOR('',#901,1.);
#903=CARTESIAN_POINT('',(19.2,13.6,-30.2));
#904=LINE('',#903,#902);
#905=EDGE_CURVE('E794',#882,#898,#904,.F.);
#906=ORIENTED_EDGE('',*,*,#905,.F.);
#907=EDGE_LOOP('',(#884,#892,#900,#906));
#908=FACE_BOUND('',#907,.T.);
#909=ADVANCED_FACE('F539',(#908),#874,.F.);
#910=CARTESIAN_POINT('',(-19.2,13.6,-30.2));
#911=DIRECTION('',(0.707106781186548,-0.707106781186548,0.));
#912=DIRECTION('',(0.707106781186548,0.707106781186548,0.));
#913=AXIS2_PLACEMENT_3D('',#910,#911,#912);
#914=PLANE('',#913);
#915=DIRECTION('',(-0.707106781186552,-0.707106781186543,0.));
#916=VECTOR('',#915,1.);
#917=CARTESIAN_POINT('',(-19.2,13.6,-22.8));
#918=LINE('',#917,#916);
#919=CARTESIAN_POINT('',(-19.2,13.6,-22.8));
#920=VERTEX_POINT('',#919);
#921=CARTESIAN_POINT('',(-19.6,13.2,-22.8));
#922=VERTEX_POINT('',#921);
#923=EDGE_CURVE('E690',#920,#922,#918,.T.);
#924=ORIENTED_EDGE('',*,*,#923,.F.);
#925=DIRECTION('',(0.,0.,1.));
#926=VECTOR('',#925,1.);
#927=CARTESIAN_POINT('',(-19.2,13.6,-30.2));
#928=LINE('',#927,#926);
#929=CARTESIAN_POINT('',(-19.2,13.6,-30.2));
#930=VERTEX_POINT('',#929);
#931=EDGE_CURVE('E787',#930,#920,#928,.T.);
#932=ORIENTED_EDGE('',*,*,#931,.F.);
#933=DIRECTION('',(0.707106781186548,0.707106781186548,0.));
#934=VECTOR('',#933,1.);
#935=CARTESIAN_POINT('',(-19.2,13.6,-30.2));
#936=LINE('',#935,#934);
#937=CARTESIAN_POINT('',(-19.6,13.2,-30.2));
#938=VERTEX_POINT('',#937);
#939=EDGE_CURVE('E680',#938,#930,#936,.T.);
#940=ORIENTED_EDGE('',*,*,#939,.F.);
#941=DIRECTION('',(0.,0.,1.));
#942=VECTOR('',#941,1.);
#943=CARTESIAN_POINT('',(-19.6,13.2,-30.2));
#944=LINE('',#943,#942);
#945=EDGE_CURVE('E799',#922,#938,#944,.F.);
#946=ORIENTED_EDGE('',*,*,#945,.F.);
#947=EDGE_LOOP('',(#924,#932,#940,#946));
#948=FACE_BOUND('',#947,.T.);
#949=ADVANCED_FACE('F536',(#948),#914,.F.);
#950=CARTESIAN_POINT('',(20.,14.,-22.8));
#951=DIRECTION('',(0.,0.,-1.));
#952=DIRECTION('',(-1.,0.,0.));
#953=AXIS2_PLACEMENT_3D('',#950,#951,#952);
#954=PLANE('',#953);
#955=ORIENTED_EDGE('',*,*,#504,.T.);
#956=ORIENTED_EDGE('',*,*,#340,.T.);
#957=ORIENTED_EDGE('',*,*,#411,.T.);
#958=ORIENTED_EDGE('',*,*,#746,.T.);
#959=DIRECTION('',(1.,0.,0.));
#960=VECTOR('',#959,1.);
#961=CARTESIAN_POINT('',(20.,3.4,-22.8));
#962=LINE('',#961,#960);
#963=EDGE_CURVE('E337',#840,#745,#962,.T.);
#964=ORIENTED_EDGE('',*,*,#963,.F.);
#965=ORIENTED_EDGE('',*,*,#843,.T.);
#966=DIRECTION('',(0.,1.,0.));
#967=VECTOR('',#966,1.);
#968=CARTESIAN_POINT('',(19.6,3.4,-22.8));
#969=LINE('',#968,#967);
#970=EDGE_CURVE('E790',#880,#842,#969,.F.);
#971=ORIENTED_EDGE('',*,*,#970,.F.);
#972=ORIENTED_EDGE('',*,*,#883,.T.);
#973=DIRECTION('',(1.,0.,0.));
#974=VECTOR('',#973,1.);
#975=CARTESIAN_POINT('',(20.,13.6,-22.8));
#976=LINE('',#975,#974);
#977=EDGE_CURVE('E795',#920,#882,#976,.T.);
#978=ORIENTED_EDGE('',*,*,#977,.F.);
#979=ORIENTED_EDGE('',*,*,#923,.T.);
#980=DIRECTION('',(0.,1.,0.));
#981=VECTOR('',#980,1.);
#982=CARTESIAN_POINT('',(-19.6,13.6,-22.8));
#983=LINE('',#982,#981);
#984=CARTESIAN_POINT('',(-19.6,3.8,-22.8));
#985=VERTEX_POINT('',#984);
#986=EDGE_CURVE('E805',#985,#922,#983,.T.);
#987=ORIENTED_EDGE('',*,*,#986,.F.);
#988=DIRECTION('',(-0.707106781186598,0.707106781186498,0.));
#989=VECTOR('',#988,1.);
#990=CARTESIAN_POINT('',(-19.6,3.8,-22.8));
#991=LINE('',#990,#989);
#992=CARTESIAN_POINT('',(-19.2,3.40000000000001,-22.8));
#993=VERTEX_POINT('',#992);
#994=EDGE_CURVE('E658',#985,#993,#991,.F.);
#995=ORIENTED_EDGE('',*,*,#994,.T.);
#996=DIRECTION('',(-1.,0.,0.));
#997=VECTOR('',#996,1.);
#998=CARTESIAN_POINT('',(20.,3.4,-22.8));
#999=LINE('',#998,#997);
#1000=CARTESIAN_POINT('',(-19.6,3.4,-22.8));
#1001=VERTEX_POINT('',#1000);
#1002=EDGE_CURVE('E688',#993,#1001,#999,.T.);
#1003=ORIENTED_EDGE('',*,*,#1002,.T.);
#1004=DIRECTION('',(-0.707106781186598,0.707106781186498,0.));
#1005=VECTOR('',#1004,1.);
#1006=CARTESIAN_POINT('',(-19.6,3.4,-22.8));
#1007=LINE('',#1006,#1005);
#1008=EDGE_CURVE('E717',#1001,#526,#1007,.T.);
#1009=ORIENTED_EDGE('',*,*,#1008,.T.);
#1010=ORIENTED_EDGE('',*,*,#542,.T.);
#1011=ORIENTED_EDGE('',*,*,#358,.T.);
#1012=ORIENTED_EDGE('',*,*,#432,.T.);
#1013=ORIENTED_EDGE('',*,*,#178,.T.);
#1014=ORIENTED_EDGE('',*,*,#454,.T.);
#1015=ORIENTED_EDGE('',*,*,#196,.F.);
#1016=ORIENTED_EDGE('',*,*,#489,.T.);
#1017=ORIENTED_EDGE('',*,*,#276,.T.);
#1018=EDGE_LOOP('',(#955,#956,#957,#958,#964,#965,#971,#972,#978,#979,#987,#995,#1003,#1009,
#1010,#1011,#1012,#1013,#1014,#1015,#1016,#1017));
#1019=FACE_BOUND('',#1018,.T.);
#1020=ADVANCED_FACE('F535',(#1019),#954,.T.);
#1021=CARTESIAN_POINT('',(-19.6,3.8,-30.2));
#1022=DIRECTION('',(0.707106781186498,0.707106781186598,0.));
#1023=DIRECTION('',(-0.707106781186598,0.707106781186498,0.));
#1024=AXIS2_PLACEMENT_3D('',#1021,#1022,#1023);
#1025=PLANE('',#1024);
#1026=ORIENTED_EDGE('',*,*,#994,.F.);
#1027=DIRECTION('',(0.,0.,1.));
#1028=VECTOR('',#1027,1.);
#1029=CARTESIAN_POINT('',(-19.6,3.8,-30.2));
#1030=LINE('',#1029,#1028);
#1031=CARTESIAN_POINT('',(-19.6,3.8,-30.2));
#1032=VERTEX_POINT('',#1031);
#1033=EDGE_CURVE('E803',#1032,#985,#1030,.T.);
#1034=ORIENTED_EDGE('',*,*,#1033,.F.);
#1035=DIRECTION('',(-0.707106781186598,0.707106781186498,0.));
#1036=VECTOR('',#1035,1.);
#1037=CARTESIAN_POINT('',(-19.6,3.8,-30.2));
#1038=LINE('',#1037,#1036);
#1039=CARTESIAN_POINT('',(-19.2,3.40000000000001,-30.2));
#1040=VERTEX_POINT('',#1039);
#1041=EDGE_CURVE('E702',#1040,#1032,#1038,.T.);
#1042=ORIENTED_EDGE('',*,*,#1041,.F.);
#1043=DIRECTION('',(0.,0.,-1.));
#1044=VECTOR('',#1043,1.);
#1045=CARTESIAN_POINT('',(-19.2,3.4,30.2));
#1046=LINE('',#1045,#1044);
#1047=EDGE_CURVE('E255',#993,#1040,#1046,.T.);
#1048=ORIENTED_EDGE('',*,*,#1047,.F.);
#1049=EDGE_LOOP('',(#1026,#1034,#1042,#1048));
#1050=FACE_BOUND('',#1049,.T.);
#1051=ADVANCED_FACE('F526',(#1050),#1025,.F.);
#1052=CARTESIAN_POINT('',(-12.,4.75,55.));
#1053=DIRECTION('',(1.,0.,0.));
#1054=DIRECTION('',(0.,0.,-1.));
#1055=AXIS2_PLACEMENT_3D('',#1052,#1053,#1054);
#1056=PLANE('',#1055);
#1057=DIRECTION('',(0.,0.,-1.));
#1058=VECTOR('',#1057,1.);
#1059=CARTESIAN_POINT('',(-12.,3.4,30.2));
#1060=LINE('',#1059,#1058);
#1061=CARTESIAN_POINT('',(-12.,3.4,-30.2));
#1062=VERTEX_POINT('',#1061);
#1063=CARTESIAN_POINT('',(-12.,3.4,30.2));
#1064=VERTEX_POINT('',#1063);
#1065=EDGE_CURVE('E248',#1062,#1064,#1060,.F.);
#1066=ORIENTED_EDGE('',*,*,#1065,.F.);
#1067=DIRECTION('',(0.,1.,0.));
#1068=VECTOR('',#1067,1.);
#1069=CARTESIAN_POINT('',(-12.,4.75,-30.2));
#1070=LINE('',#1069,#1068);
#1071=CARTESIAN_POINT('',(-12.,4.75,-30.2));
#1072=VERTEX_POINT('',#1071);
#1073=EDGE_CURVE('E655',#1062,#1072,#1070,.T.);
#1074=ORIENTED_EDGE('',*,*,#1073,.T.);
#1075=DIRECTION('',(0.,0.,-1.));
#1076=VECTOR('',#1075,1.);
#1077=CARTESIAN_POINT('',(-12.,4.75,55.));
#1078=LINE('',#1077,#1076);
#1079=CARTESIAN_POINT('',(-12.,4.75,30.2));
#1080=VERTEX_POINT('',#1079);
#1081=EDGE_CURVE('E648',#1080,#1072,#1078,.T.);
#1082=ORIENTED_EDGE('',*,*,#1081,.F.);
#1083=DIRECTION('',(0.,1.,0.));
#1084=VECTOR('',#1083,1.);
#1085=CARTESIAN_POINT('',(-12.,4.75,30.2));
#1086=LINE('',#1085,#1084);
#1087=EDGE_CURVE('E654',#1080,#1064,#1086,.F.);
#1088=ORIENTED_EDGE('',*,*,#1087,.T.);
#1089=EDGE_LOOP('',(#1066,#1074,#1082,#1088));
#1090=FACE_BOUND('',#1089,.T.);
#1091=ADVANCED_FACE('F521',(#1090),#1056,.T.);
#1092=CARTESIAN_POINT('',(-19.2,3.4,30.2));
#1093=DIRECTION('',(0.707106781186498,0.707106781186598,0.));
#1094=DIRECTION('',(-0.707106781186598,0.707106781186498,0.));
#1095=AXIS2_PLACEMENT_3D('',#1092,#1093,#1094);
#1096=PLANE('',#1095);
#1097=ORIENTED_EDGE('',*,*,#696,.F.);
#1098=DIRECTION('',(0.,0.,-1.));
#1099=VECTOR('',#1098,1.);
#1100=CARTESIAN_POINT('',(-19.2,3.4,30.2));
#1101=LINE('',#1100,#1099);
#1102=CARTESIAN_POINT('',(-19.2,3.4,30.2));
#1103=VERTEX_POINT('',#1102);
#1104=EDGE_CURVE('E251',#1103,#687,#1101,.T.);
#1105=ORIENTED_EDGE('',*,*,#1104,.F.);
#1106=DIRECTION('',(-0.707106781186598,0.707106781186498,0.));
#1107=VECTOR('',#1106,1.);
#1108=CARTESIAN_POINT('',(-19.2,3.4,30.2));
#1109=LINE('',#1108,#1107);
#1110=CARTESIAN_POINT('',(-19.6,3.79999999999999,30.2));
#1111=VERTEX_POINT('',#1110);
#1112=EDGE_CURVE('E652',#1111,#1103,#1109,.F.);
#1113=ORIENTED_EDGE('',*,*,#1112,.F.);
#1114=DIRECTION('',(0.,0.,1.));
#1115=VECTOR('',#1114,1.);
#1116=CARTESIAN_POINT('',(-19.6,3.8,30.2));
#1117=LINE('',#1116,#1115);
#1118=EDGE_CURVE('E744',#695,#1111,#1117,.T.);
#1119=ORIENTED_EDGE('',*,*,#1118,.F.);
#1120=EDGE_LOOP('',(#1097,#1105,#1113,#1119));
#1121=FACE_BOUND('',#1120,.T.);
#1122=ADVANCED_FACE('F519',(#1121),#1096,.F.);
#1123=CARTESIAN_POINT('',(-19.6,3.4,30.2));
#1124=DIRECTION('',(0.707106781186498,0.707106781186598,0.));
#1125=DIRECTION('',(-0.707106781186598,0.707106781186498,0.));
#1126=AXIS2_PLACEMENT_3D('',#1123,#1124,#1125);
#1127=PLANE('',#1126);
#1128=ORIENTED_EDGE('',*,*,#1008,.F.);
#1129=DIRECTION('',(0.,0.,-1.));
#1130=VECTOR('',#1129,1.);
#1131=CARTESIAN_POINT('',(-19.6,3.4,30.2));
#1132=LINE('',#1131,#1130);
#1133=EDGE_CURVE('E726',#679,#1001,#1132,.T.);
#1134=ORIENTED_EDGE('',*,*,#1133,.F.);
#1135=ORIENTED_EDGE('',*,*,#680,.F.);
#1136=ORIENTED_EDGE('',*,*,#529,.F.);
#1137=EDGE_LOOP('',(#1128,#1134,#1135,#1136));
#1138=FACE_BOUND('',#1137,.T.);
#1139=ADVANCED_FACE('F516',(#1138),#1127,.F.);
#1140=CARTESIAN_POINT('',(0.,11.2,-25.1999999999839));
#1141=DIRECTION('',(0.,0.,-1.));
#1142=DIRECTION('',(-1.,0.,0.));
#1143=AXIS2_PLACEMENT_3D('',#1140,#1141,#1142);
#1144=CONICAL_SURFACE('',#1143,0.699999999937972,1.0297442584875);
#1145=CARTESIAN_POINT('',(0.,11.2,-24.7793975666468));
#1146=VERTEX_POINT('',#1145);
#1147=VERTEX_LOOP('',#1146);
#1148=FACE_BOUND('',#1147,.T.);
#1149=CARTESIAN_POINT('',(0.,11.2,-25.2));
#1150=DIRECTION('',(0.,0.,1.));
#1151=DIRECTION('',(1.,0.,0.));
#1152=AXIS2_PLACEMENT_3D('',#1149,#1150,#1151);
#1153=CIRCLE('',#1152,0.7);
#1154=CARTESIAN_POINT('',(0.7,11.2,-25.2));
#1155=VERTEX_POINT('',#1154);
#1156=EDGE_CURVE('E724',#1155,#1155,#1153,.F.);
#1157=ORIENTED_EDGE('',*,*,#1156,.T.);
#1158=EDGE_LOOP('',(#1157));
#1159=FACE_BOUND('',#1158,.T.);
#1160=ADVANCED_FACE('F511',(#1148,#1159),#1144,.F.);
#1161=CARTESIAN_POINT('',(19.6,3.4,30.2));
#1162=DIRECTION('',(-1.,0.,0.));
#1163=DIRECTION('',(0.,0.,1.));
#1164=AXIS2_PLACEMENT_3D('',#1161,#1162,#1163);
#1165=PLANE('',#1164);
#1166=ORIENTED_EDGE('',*,*,#639,.F.);
#1167=ORIENTED_EDGE('',*,*,#576,.F.);
#1168=DIRECTION('',(0.,1.,0.));
#1169=VECTOR('',#1168,1.);
#1170=CARTESIAN_POINT('',(19.6,10.5,30.2));
#1171=LINE('',#1170,#1169);
#1172=EDGE_CURVE('E322',#769,#567,#1171,.T.);
#1173=ORIENTED_EDGE('',*,*,#1172,.F.);
#1174=ORIENTED_EDGE('',*,*,#770,.F.);
#1175=EDGE_LOOP('',(#1166,#1167,#1173,#1174));
#1176=FACE_BOUND('',#1175,.T.);
#1177=ADVANCED_FACE('F510',(#1176),#1165,.F.);
#1178=CARTESIAN_POINT('',(-20.,13.6,30.2));
#1179=DIRECTION('',(0.,1.,0.));
#1180=DIRECTION('',(0.,0.,1.));
#1181=AXIS2_PLACEMENT_3D('',#1178,#1179,#1180);
#1182=PLANE('',#1181);
#1183=ORIENTED_EDGE('',*,*,#560,.T.);
#1184=ORIENTED_EDGE('',*,*,#709,.T.);
#1185=ORIENTED_EDGE('',*,*,#622,.T.);
#1186=DIRECTION('',(1.,0.,0.));
#1187=VECTOR('',#1186,1.);
#1188=CARTESIAN_POINT('',(20.,13.6,30.2));
#1189=LINE('',#1188,#1187);
#1190=EDGE_CURVE('E817',#557,#615,#1189,.F.);
#1191=ORIENTED_EDGE('',*,*,#1190,.F.);
#1192=EDGE_LOOP('',(#1183,#1184,#1185,#1191));
#1193=FACE_BOUND('',#1192,.T.);
#1194=ADVANCED_FACE('F503',(#1193),#1182,.T.);
#1195=CARTESIAN_POINT('',(-19.6,3.4,30.2));
#1196=DIRECTION('',(-1.,0.,0.));
#1197=DIRECTION('',(0.,0.,1.));
#1198=AXIS2_PLACEMENT_3D('',#1195,#1196,#1197);
#1199=PLANE('',#1198);
#1200=ORIENTED_EDGE('',*,*,#608,.T.);
#1201=ORIENTED_EDGE('',*,*,#702,.T.);
#1202=ORIENTED_EDGE('',*,*,#1118,.T.);
#1203=DIRECTION('',(0.,1.,0.));
#1204=VECTOR('',#1203,1.);
#1205=CARTESIAN_POINT('',(-19.6,10.5,30.2));
#1206=LINE('',#1205,#1204);
#1207=EDGE_CURVE('E268',#607,#1111,#1206,.F.);
#1208=ORIENTED_EDGE('',*,*,#1207,.F.);
#1209=EDGE_LOOP('',(#1200,#1201,#1202,#1208));
#1210=FACE_BOUND('',#1209,.T.);
#1211=ADVANCED_FACE('F498',(#1210),#1199,.T.);
#1212=CARTESIAN_POINT('',(0.,11.2,30.2));
#1213=DIRECTION('',(0.,0.,-1.));
#1214=DIRECTION('',(-1.,0.,0.));
#1215=AXIS2_PLACEMENT_3D('',#1212,#1213,#1214);
#1216=CYLINDRICAL_SURFACE('',#1215,0.7);
#1217=CARTESIAN_POINT('',(0.,11.2,30.2));
#1218=DIRECTION('',(0.,0.,-1.));
#1219=DIRECTION('',(-1.,0.,0.));
#1220=AXIS2_PLACEMENT_3D('',#1217,#1218,#1219);
#1221=CIRCLE('',#1220,0.7);
#1222=CARTESIAN_POINT('',(-0.7,11.2,30.2));
#1223=VERTEX_POINT('',#1222);
#1224=EDGE_CURVE('E395',#1223,#1223,#1221,.T.);
#1225=ORIENTED_EDGE('',*,*,#1224,.F.);
#1226=EDGE_LOOP('',(#1225));
#1227=FACE_BOUND('',#1226,.T.);
#1228=ORIENTED_EDGE('',*,*,#730,.F.);
#1229=EDGE_LOOP('',(#1228));
#1230=FACE_BOUND('',#1229,.T.);
#1231=ADVANCED_FACE('F497',(#1227,#1230),#1216,.F.);
#1232=CARTESIAN_POINT('',(-12.,6.,55.));
#1233=DIRECTION('',(0.,0.,-1.));
#1234=DIRECTION('',(-1.,0.,0.));
#1235=AXIS2_PLACEMENT_3D('',#1232,#1233,#1234);
#1236=CYLINDRICAL_SURFACE('',#1235,1.25);
#1237=ORIENTED_EDGE('',*,*,#1081,.T.);
#1238=CARTESIAN_POINT('',(-12.,6.,-30.2));
#1239=DIRECTION('',(0.,0.,-1.));
#1240=DIRECTION('',(-1.,0.,0.));
#1241=AXIS2_PLACEMENT_3D('',#1238,#1239,#1240);
#1242=CIRCLE('',#1241,1.25);
#1243=CARTESIAN_POINT('',(-12.,7.25,-30.2));
#1244=VERTEX_POINT('',#1243);
#1245=EDGE_CURVE('E392',#1072,#1244,#1242,.F.);
#1246=ORIENTED_EDGE('',*,*,#1245,.T.);
#1247=DIRECTION('',(0.,0.,-1.));
#1248=VECTOR('',#1247,1.);
#1249=CARTESIAN_POINT('',(-12.,7.25,55.));
#1250=LINE('',#1249,#1248);
#1251=CARTESIAN_POINT('',(-12.,7.25,30.2));
#1252=VERTEX_POINT('',#1251);
#1253=EDGE_CURVE('E393',#1252,#1244,#1250,.T.);
#1254=ORIENTED_EDGE('',*,*,#1253,.F.);
#1255=CARTESIAN_POINT('',(-12.,6.,30.2));
#1256=DIRECTION('',(0.,0.,-1.));
#1257=DIRECTION('',(-1.,0.,0.));
#1258=AXIS2_PLACEMENT_3D('',#1255,#1256,#1257);
#1259=CIRCLE('',#1258,1.25);
#1260=EDGE_CURVE('E270',#1080,#1252,#1259,.F.);
#1261=ORIENTED_EDGE('',*,*,#1260,.F.);
#1262=EDGE_LOOP('',(#1237,#1246,#1254,#1261));
#1263=FACE_BOUND('',#1262,.T.);
#1264=ADVANCED_FACE('F495',(#1263),#1236,.T.);
#1265=CARTESIAN_POINT('',(12.,6.,55.));
#1266=DIRECTION('',(0.,0.,-1.));
#1267=DIRECTION('',(-1.,0.,0.));
#1268=AXIS2_PLACEMENT_3D('',#1265,#1266,#1267);
#1269=CYLINDRICAL_SURFACE('',#1268,1.25);
#1270=DIRECTION('',(0.,0.,1.));
#1271=VECTOR('',#1270,1.);
#1272=CARTESIAN_POINT('',(12.,7.25,55.));
#1273=LINE('',#1272,#1271);
#1274=CARTESIAN_POINT('',(12.,7.25,-30.2));
#1275=VERTEX_POINT('',#1274);
#1276=CARTESIAN_POINT('',(12.,7.25,30.2));
#1277=VERTEX_POINT('',#1276);
#1278=EDGE_CURVE('E729',#1275,#1277,#1273,.T.);
#1279=ORIENTED_EDGE('',*,*,#1278,.F.);
#1280=CARTESIAN_POINT('',(12.,6.,-30.2));
#1281=DIRECTION('',(0.,0.,-1.));
#1282=DIRECTION('',(-1.,0.,0.));
#1283=AXIS2_PLACEMENT_3D('',#1280,#1281,#1282);
#1284=CIRCLE('',#1283,1.25);
#1285=EDGE_CURVE('E318',#1275,#800,#1284,.F.);
#1286=ORIENTED_EDGE('',*,*,#1285,.T.);
#1287=ORIENTED_EDGE('',*,*,#803,.T.);
#1288=CARTESIAN_POINT('',(12.,6.,30.2));
#1289=DIRECTION('',(0.,0.,-1.));
#1290=DIRECTION('',(-1.,0.,0.));
#1291=AXIS2_PLACEMENT_3D('',#1288,#1289,#1290);
#1292=CIRCLE('',#1291,1.25);
#1293=EDGE_CURVE('E324',#1277,#802,#1292,.F.);
#1294=ORIENTED_EDGE('',*,*,#1293,.F.);
#1295=EDGE_LOOP('',(#1279,#1286,#1287,#1294));
#1296=FACE_BOUND('',#1295,.T.);
#1297=ADVANCED_FACE('F488',(#1296),#1269,.T.);
#1298=CARTESIAN_POINT('',(20.,3.4,30.2));
#1299=DIRECTION('',(0.,-1.,0.));
#1300=DIRECTION('',(0.,0.,-1.));
#1301=AXIS2_PLACEMENT_3D('',#1298,#1299,#1300);
#1302=PLANE('',#1301);
#1303=ORIENTED_EDGE('',*,*,#819,.T.);
#1304=DIRECTION('',(1.,0.,0.));
#1305=VECTOR('',#1304,1.);
#1306=CARTESIAN_POINT('',(20.,3.4,-30.2));
#1307=LINE('',#1306,#1305);
#1308=EDGE_CURVE('E314',#810,#850,#1307,.T.);
#1309=ORIENTED_EDGE('',*,*,#1308,.T.);
#1310=ORIENTED_EDGE('',*,*,#851,.T.);
#1311=ORIENTED_EDGE('',*,*,#963,.T.);
#1312=ORIENTED_EDGE('',*,*,#754,.T.);
#1313=ORIENTED_EDGE('',*,*,#655,.F.);
#1314=ORIENTED_EDGE('',*,*,#784,.T.);
#1315=DIRECTION('',(1.,0.,0.));
#1316=VECTOR('',#1315,1.);
#1317=CARTESIAN_POINT('',(20.,3.4,30.2));
#1318=LINE('',#1317,#1316);
#1319=EDGE_CURVE('E321',#818,#777,#1318,.T.);
#1320=ORIENTED_EDGE('',*,*,#1319,.F.);
#1321=EDGE_LOOP('',(#1303,#1309,#1310,#1311,#1312,#1313,#1314,#1320));
#1322=FACE_BOUND('',#1321,.T.);
#1323=ADVANCED_FACE('F482',(#1322),#1302,.T.);
#1324=CARTESIAN_POINT('',(19.6,3.4,-30.2));
#1325=DIRECTION('',(1.,0.,0.));
#1326=DIRECTION('',(0.,0.,-1.));
#1327=AXIS2_PLACEMENT_3D('',#1324,#1325,#1326);
#1328=PLANE('',#1327);
#1329=ORIENTED_EDGE('',*,*,#891,.T.);
#1330=ORIENTED_EDGE('',*,*,#970,.T.);
#1331=ORIENTED_EDGE('',*,*,#865,.T.);
#1332=DIRECTION('',(0.,1.,0.));
#1333=VECTOR('',#1332,1.);
#1334=CARTESIAN_POINT('',(19.6,10.5,-30.2));
#1335=LINE('',#1334,#1333);
#1336=EDGE_CURVE('E320',#858,#890,#1335,.T.);
#1337=ORIENTED_EDGE('',*,*,#1336,.T.);
#1338=EDGE_LOOP('',(#1329,#1330,#1331,#1337));
#1339=FACE_BOUND('',#1338,.T.);
#1340=ADVANCED_FACE('F477',(#1339),#1328,.T.);
#1341=CARTESIAN_POINT('',(20.,13.6,-30.2));
#1342=DIRECTION('',(0.,1.,0.));
#1343=DIRECTION('',(0.,0.,1.));
#1344=AXIS2_PLACEMENT_3D('',#1341,#1342,#1343);
#1345=PLANE('',#1344);
#1346=ORIENTED_EDGE('',*,*,#905,.T.);
#1347=DIRECTION('',(1.,0.,0.));
#1348=VECTOR('',#1347,1.);
#1349=CARTESIAN_POINT('',(20.,13.6,-30.2));
#1350=LINE('',#1349,#1348);
#1351=EDGE_CURVE('E834',#898,#930,#1350,.F.);
#1352=ORIENTED_EDGE('',*,*,#1351,.T.);
#1353=ORIENTED_EDGE('',*,*,#931,.T.);
#1354=ORIENTED_EDGE('',*,*,#977,.T.);
#1355=EDGE_LOOP('',(#1346,#1352,#1353,#1354));
#1356=FACE_BOUND('',#1355,.T.);
#1357=ADVANCED_FACE('F478',(#1356),#1345,.T.);
#1358=CARTESIAN_POINT('',(-19.6,13.6,-30.2));
#1359=DIRECTION('',(-1.,0.,0.));
#1360=DIRECTION('',(0.,0.,1.));
#1361=AXIS2_PLACEMENT_3D('',#1358,#1359,#1360);
#1362=PLANE('',#1361);
#1363=ORIENTED_EDGE('',*,*,#1033,.T.);
#1364=ORIENTED_EDGE('',*,*,#986,.T.);
#1365=ORIENTED_EDGE('',*,*,#945,.T.);
#1366=DIRECTION('',(0.,1.,0.));
#1367=VECTOR('',#1366,1.);
#1368=CARTESIAN_POINT('',(-19.6,10.5,-30.2));
#1369=LINE('',#1368,#1367);
#1370=EDGE_CURVE('E261',#938,#1032,#1369,.F.);
#1371=ORIENTED_EDGE('',*,*,#1370,.T.);
#1372=EDGE_LOOP('',(#1363,#1364,#1365,#1371));
#1373=FACE_BOUND('',#1372,.T.);
#1374=ADVANCED_FACE('F472',(#1373),#1362,.T.);
#1375=CARTESIAN_POINT('',(20.,3.4,30.2));
#1376=DIRECTION('',(0.,-1.,0.));
#1377=DIRECTION('',(0.,0.,-1.));
#1378=AXIS2_PLACEMENT_3D('',#1375,#1376,#1377);
#1379=PLANE('',#1378);
#1380=ORIENTED_EDGE('',*,*,#1133,.T.);
#1381=ORIENTED_EDGE('',*,*,#1002,.F.);
#1382=ORIENTED_EDGE('',*,*,#1047,.T.);
#1383=DIRECTION('',(1.,0.,0.));
#1384=VECTOR('',#1383,1.);
#1385=CARTESIAN_POINT('',(20.,3.4,-30.2));
#1386=LINE('',#1385,#1384);
#1387=EDGE_CURVE('E260',#1040,#1062,#1386,.T.);
#1388=ORIENTED_EDGE('',*,*,#1387,.T.);
#1389=ORIENTED_EDGE('',*,*,#1065,.T.);
#1390=DIRECTION('',(1.,0.,0.));
#1391=VECTOR('',#1390,1.);
#1392=CARTESIAN_POINT('',(20.,3.4,30.2));
#1393=LINE('',#1392,#1391);
#1394=EDGE_CURVE('E262',#1103,#1064,#1393,.T.);
#1395=ORIENTED_EDGE('',*,*,#1394,.F.);
#1396=ORIENTED_EDGE('',*,*,#1104,.T.);
#1397=ORIENTED_EDGE('',*,*,#688,.F.);
#1398=EDGE_LOOP('',(#1380,#1381,#1382,#1388,#1389,#1395,#1396,#1397));
#1399=FACE_BOUND('',#1398,.T.);
#1400=ADVANCED_FACE('F469',(#1399),#1379,.T.);
#1401=CARTESIAN_POINT('',(0.,11.2,-30.2));
#1402=DIRECTION('',(0.,0.,1.));
#1403=DIRECTION('',(1.,0.,0.));
#1404=AXIS2_PLACEMENT_3D('',#1401,#1402,#1403);
#1405=CYLINDRICAL_SURFACE('',#1404,0.7);
#1406=CARTESIAN_POINT('',(0.,11.2,-30.2));
#1407=DIRECTION('',(0.,0.,1.));
#1408=DIRECTION('',(1.,0.,0.));
#1409=AXIS2_PLACEMENT_3D('',#1406,#1407,#1408);
#1410=CIRCLE('',#1409,0.7);
#1411=CARTESIAN_POINT('',(0.7,11.2,-30.2));
#1412=VERTEX_POINT('',#1411);
#1413=EDGE_CURVE('E257',#1412,#1412,#1410,.F.);
#1414=ORIENTED_EDGE('',*,*,#1413,.T.);
#1415=EDGE_LOOP('',(#1414));
#1416=FACE_BOUND('',#1415,.T.);
#1417=ORIENTED_EDGE('',*,*,#1156,.F.);
#1418=EDGE_LOOP('',(#1417));
#1419=FACE_BOUND('',#1418,.T.);
#1420=ADVANCED_FACE('F463',(#1416,#1419),#1405,.F.);
#1421=CARTESIAN_POINT('',(12.,7.25,55.));
#1422=DIRECTION('',(-1.,0.,0.));
#1423=DIRECTION('',(0.,0.,1.));
#1424=AXIS2_PLACEMENT_3D('',#1421,#1422,#1423);
#1425=PLANE('',#1424);
#1426=DIRECTION('',(0.,0.,-1.));
#1427=VECTOR('',#1426,1.);
#1428=CARTESIAN_POINT('',(12.,8.5,55.));
#1429=LINE('',#1428,#1427);
#1430=CARTESIAN_POINT('',(12.,8.5,-30.2));
#1431=VERTEX_POINT('',#1430);
#1432=CARTESIAN_POINT('',(12.,8.5,30.2));
#1433=VERTEX_POINT('',#1432);
#1434=EDGE_CURVE('E389',#1431,#1433,#1429,.F.);
#1435=ORIENTED_EDGE('',*,*,#1434,.F.);
#1436=DIRECTION('',(0.,1.,0.));
#1437=VECTOR('',#1436,1.);
#1438=CARTESIAN_POINT('',(12.,10.5,-30.2));
#1439=LINE('',#1438,#1437);
#1440=EDGE_CURVE('E391',#1431,#1275,#1439,.F.);
#1441=ORIENTED_EDGE('',*,*,#1440,.T.);
#1442=ORIENTED_EDGE('',*,*,#1278,.T.);
#1443=DIRECTION('',(0.,1.,0.));
#1444=VECTOR('',#1443,1.);
#1445=CARTESIAN_POINT('',(12.,10.5,30.2));
#1446=LINE('',#1445,#1444);
#1447=EDGE_CURVE('E401',#1433,#1277,#1446,.F.);
#1448=ORIENTED_EDGE('',*,*,#1447,.F.);
#1449=EDGE_LOOP('',(#1435,#1441,#1442,#1448));
#1450=FACE_BOUND('',#1449,.T.);
#1451=ADVANCED_FACE('F459',(#1450),#1425,.T.);
#1452=CARTESIAN_POINT('',(20.,10.5,30.2));
#1453=DIRECTION('',(0.,0.,1.));
#1454=DIRECTION('',(1.,0.,0.));
#1455=AXIS2_PLACEMENT_3D('',#1452,#1453,#1454);
#1456=PLANE('',#1455);
#1457=ORIENTED_EDGE('',*,*,#1224,.T.);
#1458=EDGE_LOOP('',(#1457));
#1459=FACE_BOUND('',#1458,.T.);
#1460=ORIENTED_EDGE('',*,*,#1087,.F.);
#1461=ORIENTED_EDGE('',*,*,#1260,.T.);
#1462=DIRECTION('',(0.,1.,0.));
#1463=VECTOR('',#1462,1.);
#1464=CARTESIAN_POINT('',(-12.,8.5,30.2));
#1465=LINE('',#1464,#1463);
#1466=CARTESIAN_POINT('',(-12.,8.5,30.2));
#1467=VERTEX_POINT('',#1466);
#1468=EDGE_CURVE('E400',#1467,#1252,#1465,.F.);
#1469=ORIENTED_EDGE('',*,*,#1468,.F.);
#1470=DIRECTION('',(1.,0.,0.));
#1471=VECTOR('',#1470,1.);
#1472=CARTESIAN_POINT('',(12.,8.5,30.2));
#1473=LINE('',#1472,#1471);
#1474=EDGE_CURVE('E751',#1433,#1467,#1473,.F.);
#1475=ORIENTED_EDGE('',*,*,#1474,.F.);
#1476=ORIENTED_EDGE('',*,*,#1447,.T.);
#1477=ORIENTED_EDGE('',*,*,#1293,.T.);
#1478=ORIENTED_EDGE('',*,*,#825,.F.);
#1479=ORIENTED_EDGE('',*,*,#1319,.T.);
#1480=ORIENTED_EDGE('',*,*,#778,.F.);
#1481=ORIENTED_EDGE('',*,*,#1172,.T.);
#1482=ORIENTED_EDGE('',*,*,#568,.F.);
#1483=ORIENTED_EDGE('',*,*,#1190,.T.);
#1484=ORIENTED_EDGE('',*,*,#616,.T.);
#1485=ORIENTED_EDGE('',*,*,#1207,.T.);
#1486=ORIENTED_EDGE('',*,*,#1112,.T.);
#1487=ORIENTED_EDGE('',*,*,#1394,.T.);
#1488=EDGE_LOOP('',(#1460,#1461,#1469,#1475,#1476,#1477,#1478,#1479,#1480,#1481,#1482,#1483,
#1484,#1485,#1486,#1487));
#1489=FACE_BOUND('',#1488,.T.);
#1490=ADVANCED_FACE('F456',(#1459,#1489),#1456,.T.);
#1491=CARTESIAN_POINT('',(-12.,8.5,55.));
#1492=DIRECTION('',(1.,0.,0.));
#1493=DIRECTION('',(0.,0.,-1.));
#1494=AXIS2_PLACEMENT_3D('',#1491,#1492,#1493);
#1495=PLANE('',#1494);
#1496=ORIENTED_EDGE('',*,*,#1253,.T.);
#1497=DIRECTION('',(0.,1.,0.));
#1498=VECTOR('',#1497,1.);
#1499=CARTESIAN_POINT('',(-12.,10.5,-30.2));
#1500=LINE('',#1499,#1498);
#1501=CARTESIAN_POINT('',(-12.,8.5,-30.2));
#1502=VERTEX_POINT('',#1501);
#1503=EDGE_CURVE('E34',#1244,#1502,#1500,.T.);
#1504=ORIENTED_EDGE('',*,*,#1503,.T.);
#1505=DIRECTION('',(0.,0.,-1.));
#1506=VECTOR('',#1505,1.);
#1507=CARTESIAN_POINT('',(-12.,8.5,55.));
#1508=LINE('',#1507,#1506);
#1509=EDGE_CURVE('E27',#1467,#1502,#1508,.T.);
#1510=ORIENTED_EDGE('',*,*,#1509,.F.);
#1511=ORIENTED_EDGE('',*,*,#1468,.T.);
#1512=EDGE_LOOP('',(#1496,#1504,#1510,#1511));
#1513=FACE_BOUND('',#1512,.T.);
#1514=ADVANCED_FACE('F450',(#1513),#1495,.T.);
#1515=CARTESIAN_POINT('',(20.,10.5,-30.2));
#1516=DIRECTION('',(0.,0.,1.));
#1517=DIRECTION('',(1.,0.,0.));
#1518=AXIS2_PLACEMENT_3D('',#1515,#1516,#1517);
#1519=PLANE('',#1518);
#1520=ORIENTED_EDGE('',*,*,#1413,.F.);
#1521=EDGE_LOOP('',(#1520));
#1522=FACE_BOUND('',#1521,.T.);
#1523=ORIENTED_EDGE('',*,*,#1387,.F.);
#1524=ORIENTED_EDGE('',*,*,#1041,.T.);
#1525=ORIENTED_EDGE('',*,*,#1370,.F.);
#1526=ORIENTED_EDGE('',*,*,#939,.T.);
#1527=ORIENTED_EDGE('',*,*,#1351,.F.);
#1528=ORIENTED_EDGE('',*,*,#899,.T.);
#1529=ORIENTED_EDGE('',*,*,#1336,.F.);
#1530=ORIENTED_EDGE('',*,*,#859,.T.);
#1531=ORIENTED_EDGE('',*,*,#1308,.F.);
#1532=ORIENTED_EDGE('',*,*,#811,.F.);
#1533=ORIENTED_EDGE('',*,*,#1285,.F.);
#1534=ORIENTED_EDGE('',*,*,#1440,.F.);
#1535=DIRECTION('',(1.,0.,0.));
#1536=VECTOR('',#1535,1.);
#1537=CARTESIAN_POINT('',(12.,8.5,-30.2));
#1538=LINE('',#1537,#1536);
#1539=EDGE_CURVE('E11',#1502,#1431,#1538,.T.);
#1540=ORIENTED_EDGE('',*,*,#1539,.F.);
#1541=ORIENTED_EDGE('',*,*,#1503,.F.);
#1542=ORIENTED_EDGE('',*,*,#1245,.F.);
#1543=ORIENTED_EDGE('',*,*,#1073,.F.);
#1544=EDGE_LOOP('',(#1523,#1524,#1525,#1526,#1527,#1528,#1529,#1530,#1531,#1532,#1533,#1534,
#1540,#1541,#1542,#1543));
#1545=FACE_BOUND('',#1544,.T.);
#1546=ADVANCED_FACE('F444',(#1522,#1545),#1519,.F.);
#1547=CARTESIAN_POINT('',(12.,8.5,55.));
#1548=DIRECTION('',(0.,-1.,0.));
#1549=DIRECTION('',(0.,0.,-1.));
#1550=AXIS2_PLACEMENT_3D('',#1547,#1548,#1549);
#1551=PLANE('',#1550);
#1552=ORIENTED_EDGE('',*,*,#1509,.T.);
#1553=ORIENTED_EDGE('',*,*,#1539,.T.);
#1554=ORIENTED_EDGE('',*,*,#1434,.T.);
#1555=ORIENTED_EDGE('',*,*,#1474,.T.);
#1556=EDGE_LOOP('',(#1552,#1553,#1554,#1555));
#1557=FACE_BOUND('',#1556,.T.);
#1558=ADVANCED_FACE('F442',(#1557),#1551,.T.);
#1559=CLOSED_SHELL('',(#39,#60,#81,#102,#122,#142,#182,#222,#242,#262,#302,#344,#384,#415,#443,
#465,#493,#515,#546,#586,#626,#713,#734,#758,#789,#829,#869,#909,#949,#1020,#1051,#1091,#1122,
#1139,#1160,#1177,#1194,#1211,#1231,#1264,#1297,#1323,#1340,#1357,#1374,#1400,#1420,#1451,#1490,
#1514,#1546,#1558));
#1560=MANIFOLD_SOLID_BREP('B1',#1559);
#1561=ADVANCED_BREP_SHAPE_REPRESENTATION('',(#18,#1560),#14);
#1562=SHAPE_DEFINITION_REPRESENTATION(#9,#1561);
ENDSEC;
END-ISO-10303-21;
